VERSION 5.7 ;
  NOWIREEXTENSIONATPIN ON ;
  DIVIDERCHAR "/" ;
  BUSBITCHARS "[]" ;
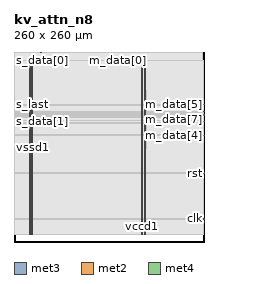
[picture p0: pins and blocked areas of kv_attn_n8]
MACRO kv_attn_n8
  CLASS BLOCK ;
  FOREIGN kv_attn_n8 ;
  ORIGIN 0.000 0.000 ;
  SIZE 260.000 BY 260.000 ;
  PIN clk
    DIRECTION INPUT ;
    USE SIGNAL ;
    ANTENNAGATEAREA 1.286700 ;
    ANTENNADIFFAREA 0.434700 ;
    PORT
      LAYER met3 ;
        RECT 259.400 31.320 260.000 31.920 ;
    END
  END clk
  PIN m_data[0]
    DIRECTION OUTPUT ;
    USE SIGNAL ;
    ANTENNADIFFAREA 0.702900 ;
    PORT
      LAYER met2 ;
        RECT 141.770 259.720 142.050 260.000 ;
    END
  END m_data[0]
  PIN m_data[1]
    DIRECTION OUTPUT ;
    USE SIGNAL ;
    ANTENNADIFFAREA 0.702900 ;
    PORT
      LAYER met2 ;
        RECT 185.010 259.720 185.290 260.000 ;
    END
  END m_data[1]
  PIN m_data[2]
    DIRECTION OUTPUT ;
    USE SIGNAL ;
    ANTENNADIFFAREA 0.702900 ;
    PORT
      LAYER met2 ;
        RECT 127.970 259.720 128.250 260.000 ;
    END
  END m_data[2]
  PIN m_data[3]
    DIRECTION OUTPUT ;
    USE SIGNAL ;
    ANTENNADIFFAREA 0.702900 ;
    PORT
      LAYER met2 ;
        RECT 203.410 259.720 203.690 260.000 ;
    END
  END m_data[3]
  PIN m_data[4]
    DIRECTION OUTPUT ;
    USE SIGNAL ;
    ANTENNADIFFAREA 0.702900 ;
    PORT
      LAYER met3 ;
        RECT 259.400 145.560 260.000 146.160 ;
    END
  END m_data[4]
  PIN m_data[5]
    DIRECTION OUTPUT ;
    USE SIGNAL ;
    ANTENNADIFFAREA 0.702900 ;
    PORT
      LAYER met3 ;
        RECT 259.400 187.720 260.000 188.320 ;
    END
  END m_data[5]
  PIN m_data[6]
    DIRECTION OUTPUT ;
    USE SIGNAL ;
    ANTENNADIFFAREA 0.702900 ;
    PORT
      LAYER met3 ;
        RECT 259.400 164.600 260.000 165.200 ;
    END
  END m_data[6]
  PIN m_data[7]
    DIRECTION OUTPUT ;
    USE SIGNAL ;
    ANTENNADIFFAREA 0.702900 ;
    PORT
      LAYER met3 ;
        RECT 259.400 178.200 260.000 178.800 ;
    END
  END m_data[7]
  PIN m_last
    DIRECTION OUTPUT ;
    USE SIGNAL ;
    ANTENNADIFFAREA 0.702900 ;
    PORT
      LAYER met2 ;
        RECT 206.170 259.720 206.450 260.000 ;
    END
  END m_last
  PIN m_ready
    DIRECTION INPUT ;
    USE SIGNAL ;
    ANTENNAGATEAREA 0.647700 ;
    ANTENNADIFFAREA 0.434700 ;
    PORT
      LAYER met3 ;
        RECT 259.400 174.120 260.000 174.720 ;
    END
  END m_ready
  PIN m_valid
    DIRECTION OUTPUT ;
    USE SIGNAL ;
    ANTENNADIFFAREA 0.702900 ;
    PORT
      LAYER met3 ;
        RECT 259.400 172.760 260.000 173.360 ;
    END
  END m_valid
  PIN rst
    DIRECTION INPUT ;
    USE SIGNAL ;
    ANTENNAGATEAREA 0.647700 ;
    ANTENNADIFFAREA 0.434700 ;
    PORT
      LAYER met3 ;
        RECT 259.400 93.880 260.000 94.480 ;
    END
  END rst
  PIN s_data[0]
    DIRECTION INPUT ;
    USE SIGNAL ;
    ANTENNAGATEAREA 0.647700 ;
    ANTENNADIFFAREA 0.434700 ;
    PORT
      LAYER met2 ;
        RECT 33.210 259.720 33.490 260.000 ;
    END
  END s_data[0]
  PIN s_data[1]
    DIRECTION INPUT ;
    USE SIGNAL ;
    ANTENNAGATEAREA 0.647700 ;
    ANTENNADIFFAREA 0.434700 ;
    PORT
      LAYER met3 ;
        RECT 0.000 164.600 0.600 165.200 ;
    END
  END s_data[1]
  PIN s_data[2]
    DIRECTION INPUT ;
    USE SIGNAL ;
    ANTENNAGATEAREA 0.647700 ;
    ANTENNADIFFAREA 0.434700 ;
    PORT
      LAYER met3 ;
        RECT 0.000 163.240 0.600 163.840 ;
    END
  END s_data[2]
  PIN s_data[3]
    DIRECTION INPUT ;
    USE SIGNAL ;
    ANTENNAGATEAREA 0.647700 ;
    ANTENNADIFFAREA 0.434700 ;
    PORT
      LAYER met3 ;
        RECT 0.000 161.880 0.600 162.480 ;
    END
  END s_data[3]
  PIN s_data[4]
    DIRECTION INPUT ;
    USE SIGNAL ;
    ANTENNAGATEAREA 0.647700 ;
    ANTENNADIFFAREA 0.434700 ;
    PORT
      LAYER met2 ;
        RECT 36.890 259.720 37.170 260.000 ;
    END
  END s_data[4]
  PIN s_data[5]
    DIRECTION INPUT ;
    USE SIGNAL ;
    ANTENNAGATEAREA 0.647700 ;
    ANTENNADIFFAREA 0.434700 ;
    PORT
      LAYER met2 ;
        RECT 32.290 259.720 32.570 260.000 ;
    END
  END s_data[5]
  PIN s_data[6]
    DIRECTION INPUT ;
    USE SIGNAL ;
    ANTENNAGATEAREA 0.647700 ;
    ANTENNADIFFAREA 0.434700 ;
    PORT
      LAYER met2 ;
        RECT 35.970 259.720 36.250 260.000 ;
    END
  END s_data[6]
  PIN s_data[7]
    DIRECTION INPUT ;
    USE SIGNAL ;
    ANTENNAGATEAREA 0.647700 ;
    ANTENNADIFFAREA 0.434700 ;
    PORT
      LAYER met2 ;
        RECT 58.970 259.720 59.250 260.000 ;
    END
  END s_data[7]
  PIN s_last
    DIRECTION INPUT ;
    USE SIGNAL ;
    ANTENNAGATEAREA 0.647700 ;
    ANTENNADIFFAREA 0.434700 ;
    PORT
      LAYER met3 ;
        RECT 0.000 176.840 0.600 177.440 ;
    END
  END s_last
  PIN s_ready
    DIRECTION OUTPUT ;
    USE SIGNAL ;
    ANTENNADIFFAREA 0.702900 ;
    PORT
      LAYER met3 ;
        RECT 0.000 172.760 0.600 173.360 ;
    END
  END s_ready
  PIN s_valid
    DIRECTION INPUT ;
    USE SIGNAL ;
    ANTENNAGATEAREA 0.647700 ;
    ANTENNADIFFAREA 0.434700 ;
    PORT
      LAYER met3 ;
        RECT 0.000 171.400 0.600 172.000 ;
    END
  END s_valid
  PIN vccd1
    DIRECTION INOUT ;
    USE POWER ;
    PORT
      LAYER met4 ;
        RECT 21.040 10.640 22.640 247.760 ;
    END
    PORT
      LAYER met4 ;
        RECT 174.640 10.640 176.240 247.760 ;
    END
  END vccd1
  PIN vssd1
    DIRECTION INOUT ;
    USE GROUND ;
    PORT
      LAYER met4 ;
        RECT 24.340 10.640 25.940 247.760 ;
    END
    PORT
      LAYER met4 ;
        RECT 177.940 10.640 179.540 247.760 ;
    END
  END vssd1
  OBS
      LAYER nwell ;
        RECT 5.330 10.795 254.570 247.710 ;
      LAYER li1 ;
        RECT 5.520 10.795 254.380 247.605 ;
      LAYER met1 ;
        RECT 0.990 10.640 258.450 247.760 ;
      LAYER met2 ;
        RECT 1.010 259.440 32.010 259.720 ;
        RECT 32.850 259.440 32.930 259.720 ;
        RECT 33.770 259.440 35.690 259.720 ;
        RECT 36.530 259.440 36.610 259.720 ;
        RECT 37.450 259.440 58.690 259.720 ;
        RECT 59.530 259.440 127.690 259.720 ;
        RECT 128.530 259.440 141.490 259.720 ;
        RECT 142.330 259.440 184.730 259.720 ;
        RECT 185.570 259.440 203.130 259.720 ;
        RECT 203.970 259.440 205.890 259.720 ;
        RECT 206.730 259.440 258.430 259.720 ;
        RECT 1.010 10.695 258.430 259.440 ;
      LAYER met3 ;
        RECT 0.600 188.720 259.400 247.685 ;
        RECT 0.600 187.320 259.000 188.720 ;
        RECT 0.600 179.200 259.400 187.320 ;
        RECT 0.600 177.840 259.000 179.200 ;
        RECT 1.000 177.800 259.000 177.840 ;
        RECT 1.000 176.440 259.400 177.800 ;
        RECT 0.600 175.120 259.400 176.440 ;
        RECT 0.600 173.760 259.000 175.120 ;
        RECT 1.000 172.360 259.000 173.760 ;
        RECT 1.000 171.000 259.400 172.360 ;
        RECT 0.600 165.600 259.400 171.000 ;
        RECT 1.000 164.200 259.000 165.600 ;
        RECT 1.000 161.480 259.400 164.200 ;
        RECT 0.600 146.560 259.400 161.480 ;
        RECT 0.600 145.160 259.000 146.560 ;
        RECT 0.600 94.880 259.400 145.160 ;
        RECT 0.600 93.480 259.000 94.880 ;
        RECT 0.600 32.320 259.400 93.480 ;
        RECT 0.600 30.920 259.000 32.320 ;
        RECT 0.600 10.715 259.400 30.920 ;
      LAYER met4 ;
        RECT 181.535 127.335 181.865 207.225 ;
  END
END kv_attn_n8
END LIBRARY

